One B-rep face of a CAD part: STEP entity #409.
In plain terms, the planar face has unit normal (1, 0, 0).
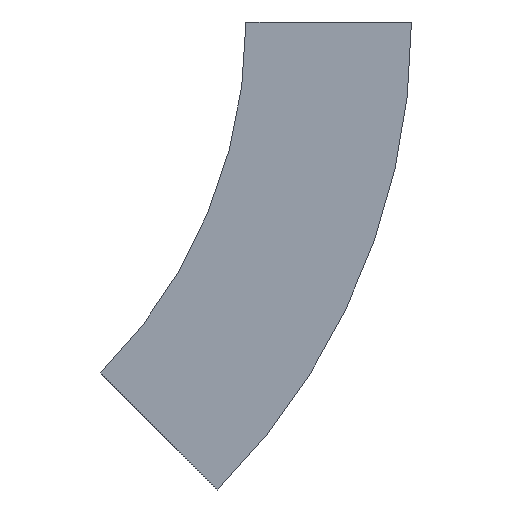
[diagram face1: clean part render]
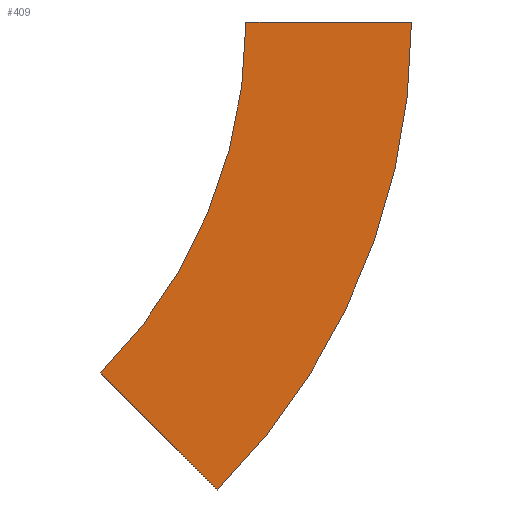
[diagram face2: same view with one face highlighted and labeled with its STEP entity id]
Its self-contained STEP definition (entity closure, numbers rounded to 3 decimals):
#9 = DIRECTION ( 'NONE',  ( 0., 1., 0. ) ) ;
#11 = CARTESIAN_POINT ( 'NONE',  ( 0., -100., 0. ) ) ;
#18 = FACE_OUTER_BOUND ( 'NONE', #147, .T. ) ;
#23 = CIRCLE ( 'NONE', #407, 400. ) ;
#39 = DIRECTION ( 'NONE',  ( 0., 0.707, 0.707 ) ) ;
#40 = DIRECTION ( 'NONE',  ( 1., 0., 0. ) ) ;
#42 = VECTOR ( 'NONE', #9, 1000. ) ;
#46 = CARTESIAN_POINT ( 'NONE',  ( 0., 0., 0. ) ) ;
#57 = CARTESIAN_POINT ( 'NONE',  ( 0., 87.868, -212.132 ) ) ;
#81 = VERTEX_POINT ( 'NONE', #46 ) ;
#85 = CARTESIAN_POINT ( 'NONE',  ( 0., 17.157, -282.843 ) ) ;
#98 = EDGE_CURVE ( 'NONE', #206, #123, #541, .T. ) ;
#104 = AXIS2_PLACEMENT_3D ( 'NONE', #464, #201, #302 ) ;
#123 = VERTEX_POINT ( 'NONE', #57 ) ;
#131 = DIRECTION ( 'NONE',  ( 0., 0., 1. ) ) ;
#147 = EDGE_LOOP ( 'NONE', ( #440, #200, #475, #503 ) ) ;
#153 = EDGE_CURVE ( 'NONE', #366, #81, #232, .T. ) ;
#169 = DIRECTION ( 'NONE',  ( 0., -1., 0. ) ) ;
#174 = CARTESIAN_POINT ( 'NONE',  ( 0., 17.157, -282.843 ) ) ;
#182 = CARTESIAN_POINT ( 'NONE',  ( 0., -100., 0. ) ) ;
#200 = ORIENTED_EDGE ( 'NONE', *, *, #153, .F. ) ;
#201 = DIRECTION ( 'NONE',  ( 1., 0., 0. ) ) ;
#206 = VERTEX_POINT ( 'NONE', #174 ) ;
#232 = LINE ( 'NONE', #495, #42 ) ;
#288 = VECTOR ( 'NONE', #39, 1000. ) ;
#302 = DIRECTION ( 'NONE',  ( 0., -1., 0. ) ) ;
#317 = AXIS2_PLACEMENT_3D ( 'NONE', #11, #532, #131 ) ;
#326 = EDGE_CURVE ( 'NONE', #366, #206, #23, .T. ) ;
#328 = EDGE_CURVE ( 'NONE', #81, #123, #361, .T. ) ;
#354 = PLANE ( 'NONE',  #317 ) ;
#361 = CIRCLE ( 'NONE', #104, 300. ) ;
#366 = VERTEX_POINT ( 'NONE', #182 ) ;
#407 = AXIS2_PLACEMENT_3D ( 'NONE', #429, #40, #169 ) ;
#409 = ADVANCED_FACE ( 'NONE', ( #18 ), #354, .F. ) ;
#429 = CARTESIAN_POINT ( 'NONE',  ( 0., 300., 0. ) ) ;
#440 = ORIENTED_EDGE ( 'NONE', *, *, #328, .F. ) ;
#464 = CARTESIAN_POINT ( 'NONE',  ( 0., 300., 0. ) ) ;
#475 = ORIENTED_EDGE ( 'NONE', *, *, #326, .T. ) ;
#495 = CARTESIAN_POINT ( 'NONE',  ( 0., -100., 0. ) ) ;
#503 = ORIENTED_EDGE ( 'NONE', *, *, #98, .T. ) ;
#532 = DIRECTION ( 'NONE',  ( -1., 0., 0. ) ) ;
#541 = LINE ( 'NONE', #85, #288 ) ;
